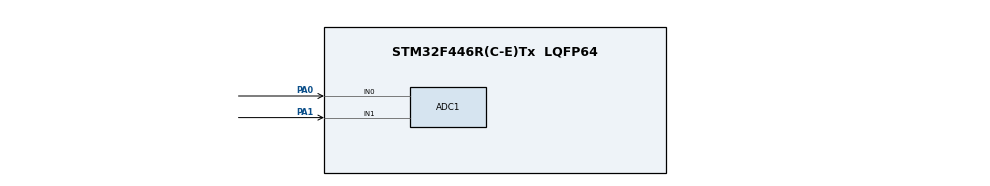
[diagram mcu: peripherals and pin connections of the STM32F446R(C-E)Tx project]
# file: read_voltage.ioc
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ADC1.Channel-0\#ChannelRegularConversion=ADC_CHANNEL_0
ADC1.Channel-1\#ChannelRegularConversion=ADC_CHANNEL_1
ADC1.ContinuousConvMode=DISABLE
ADC1.NbrOfConversion=2
ADC1.NbrOfConversionFlag=1
ADC1.Rank-0\#ChannelRegularConversion=1
ADC1.Rank-1\#ChannelRegularConversion=2
ADC1.SamplingTime-0\#ChannelRegularConversion=ADC_SAMPLETIME_28CYCLES
ADC1.SamplingTime-1\#ChannelRegularConversion=ADC_SAMPLETIME_28CYCLES
ADC1.ScanConvMode=ENABLE
ADC1.master=1
Dma.ADC1.0.Direction=DMA_PERIPH_TO_MEMORY
Dma.ADC1.0.FIFOMode=DMA_FIFOMODE_DISABLE
Dma.ADC1.0.Instance=DMA2_Stream0
Dma.ADC1.0.MemDataAlignment=DMA_MDATAALIGN_HALFWORD
Dma.ADC1.0.MemInc=DMA_MINC_ENABLE
Dma.ADC1.0.Mode=DMA_CIRCULAR
Dma.ADC1.0.PeriphDataAlignment=DMA_PDATAALIGN_HALFWORD
Dma.ADC1.0.PeriphInc=DMA_PINC_DISABLE
Dma.ADC1.0.Priority=DMA_PRIORITY_LOW
Dma.Request0=ADC1
Mcu.Family=STM32F4
Mcu.Name=STM32F446R(C-E)Tx
Mcu.Package=LQFP64
NVIC.ADC_IRQn=true\:0\:0\:true\:false\:true\:true\:true\:true
NVIC.DMA2_Stream0_IRQn=true\:0\:0\:false\:false\:true\:false\:true\:true
NVIC.PriorityGroup=NVIC_PRIORITYGROUP_0
PA0-WKUP.Signal=ADCx_IN0
PA1.Signal=ADCx_IN1
ProjectManager.HeapSize=0x200
ProjectManager.StackSize=0x400
ProjectManager.TargetToolchain=STM32CubeIDE
RCC.48MHZClocksFreq_Value=84000000
RCC.AHBFreq_Value=96000000
RCC.APB1Freq_Value=96000000
RCC.APB1TimFreq_Value=96000000
RCC.APB2Freq_Value=96000000
RCC.APB2TimFreq_Value=96000000
RCC.CortexFreq_Value=96000000
RCC.FLatency-AdvancedSettings=FLASH_LATENCY_3
RCC.HCLKFreq_Value=96000000
RCC.HSE_VALUE=8000000
RCC.HSI_VALUE=16000000
RCC.SYSCLKFreq_VALUE=96000000
RCC.SYSCLKSource=RCC_SYSCLKSOURCE_PLLCLK
RCC.USBFreq_Value=96000000
RCC.VCOOutputFreq_Value=192000000
SH.ADCx_IN0.0=ADC1_IN0,IN0
SH.ADCx_IN1.0=ADC1_IN1,IN1
board=NUCLEO-F446RE

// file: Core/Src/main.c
/* USER CODE BEGIN Header */
/**
  ******************************************************************************
  * @file           : main.c
  * @brief          : Main program body
  ******************************************************************************
  * @attention
  *
  * Copyright (c) 2024 STMicroelectronics.
  * All rights reserved.
  *
  * This software is licensed under terms that can be found in the LICENSE file
  * in the root directory of this software component.
  * If no LICENSE file comes with this software, it is provided AS-IS.
  *
  ******************************************************************************
  */
/* USER CODE END Header */
#include "main.h"

ADC_HandleTypeDef hadc1;
DMA_HandleTypeDef hdma_adc1;

void SystemClock_Config(void);
static void MX_GPIO_Init(void);
static void MX_DMA_Init(void);
static void MX_ADC1_Init(void);

int main(void)
{

  /* MCU Configuration--------------------------------------------------------*/

  /* Reset of all peripherals, Initializes the Flash interface and the Systick. */
  HAL_Init();

  /* Configure the system clock */
  SystemClock_Config();

  /* Initialize all configured peripherals */
  MX_GPIO_Init();
  MX_DMA_Init();
  MX_ADC1_Init();

  /* Infinite loop */
  while (1)
  {

  }
}

void SystemClock_Config(void)
{
  RCC_OscInitTypeDef RCC_OscInitStruct = {0};
  RCC_ClkInitTypeDef RCC_ClkInitStruct = {0};

  /** Configure the main internal regulator output voltage
  */
  __HAL_RCC_PWR_CLK_ENABLE();
  __HAL_PWR_VOLTAGESCALING_CONFIG(PWR_REGULATOR_VOLTAGE_SCALE3);

  /** Initializes the RCC Oscillators according to the specified parameters
  * in the RCC_OscInitTypeDef structure.
  */
  RCC_OscInitStruct.OscillatorType = RCC_OSCILLATORTYPE_HSE;
  RCC_OscInitStruct.HSEState = RCC_HSE_OFF;
  RCC_OscInitStruct.PLL.PLLState = RCC_PLL_ON;
  RCC_OscInitStruct.PLL.PLLSource = RCC_PLLSOURCE_HSE;
  RCC_OscInitStruct.PLL.PLLM = 16;
  RCC_OscInitStruct.PLL.PLLN = 192;
  RCC_OscInitStruct.PLL.PLLP = RCC_PLLP_DIV2;
  RCC_OscInitStruct.PLL.PLLQ = 2;
  RCC_OscInitStruct.PLL.PLLR = 2;
  if (HAL_RCC_OscConfig(&RCC_OscInitStruct) != HAL_OK)
  {
    Error_Handler();
  }

  /** Initializes the CPU, AHB and APB buses clocks
  */
  RCC_ClkInitStruct.ClockType = RCC_CLOCKTYPE_HCLK|RCC_CLOCKTYPE_SYSCLK
                              |RCC_CLOCKTYPE_PCLK1|RCC_CLOCKTYPE_PCLK2;
  RCC_ClkInitStruct.SYSCLKSource = RCC_SYSCLKSOURCE_PLLCLK;
  RCC_ClkInitStruct.AHBCLKDivider = RCC_SYSCLK_DIV1;
  RCC_ClkInitStruct.APB1CLKDivider = RCC_HCLK_DIV1;
  RCC_ClkInitStruct.APB2CLKDivider = RCC_HCLK_DIV1;

  if (HAL_RCC_ClockConfig(&RCC_ClkInitStruct, FLASH_LATENCY_1) != HAL_OK)
  {
    Error_Handler();
  }
}

static void MX_ADC1_Init(void)
{

  ADC_ChannelConfTypeDef sConfig = {0};

  /** Configure the global features of the ADC (Clock, Resolution, Data Alignment and number of conversion)
  */
  hadc1.Instance = ADC1;
  hadc1.Init.ClockPrescaler = ADC_CLOCK_SYNC_PCLK_DIV2;
  hadc1.Init.Resolution = ADC_RESOLUTION_12B;
  hadc1.Init.ScanConvMode = ENABLE;
  hadc1.Init.ContinuousConvMode = DISABLE;
  hadc1.Init.DiscontinuousConvMode = DISABLE;
  hadc1.Init.ExternalTrigConvEdge = ADC_EXTERNALTRIGCONVEDGE_NONE;
  hadc1.Init.ExternalTrigConv = ADC_SOFTWARE_START;
  hadc1.Init.DataAlign = ADC_DATAALIGN_RIGHT;
  hadc1.Init.NbrOfConversion = 2;
  hadc1.Init.DMAContinuousRequests = DISABLE;
  hadc1.Init.EOCSelection = ADC_EOC_SINGLE_CONV;
  if (HAL_ADC_Init(&hadc1) != HAL_OK)
  {
    Error_Handler();
  }

  /** Configure for the selected ADC regular channel its corresponding rank in the sequencer and its sample time.
  */
  sConfig.Channel = ADC_CHANNEL_0;
  sConfig.Rank = 1;
  sConfig.SamplingTime = ADC_SAMPLETIME_28CYCLES;
  if (HAL_ADC_ConfigChannel(&hadc1, &sConfig) != HAL_OK)
  {
    Error_Handler();
  }

  /** Configure for the selected ADC regular channel its corresponding rank in the sequencer and its sample time.
  */
  sConfig.Channel = ADC_CHANNEL_1;
  sConfig.Rank = 2;
  if (HAL_ADC_ConfigChannel(&hadc1, &sConfig) != HAL_OK)
  {
    Error_Handler();
  }

}

static void MX_DMA_Init(void)
{

  /* DMA controller clock enable */
  __HAL_RCC_DMA2_CLK_ENABLE();

  /* DMA interrupt init */
  /* DMA2_Stream0_IRQn interrupt configuration */
  HAL_NVIC_SetPriority(DMA2_Stream0_IRQn, 0, 0);
  HAL_NVIC_EnableIRQ(DMA2_Stream0_IRQn);

}

static void MX_GPIO_Init(void)
{

  /* GPIO Ports Clock Enable */
  __HAL_RCC_GPIOA_CLK_ENABLE();

}

void Error_Handler(void)
{
  __disable_irq();
  while (1)
  {
  }
}
